VERSION 5.7 ;
  NOWIREEXTENSIONATPIN ON ;
  DIVIDERCHAR "/" ;
  BUSBITCHARS "[]" ;
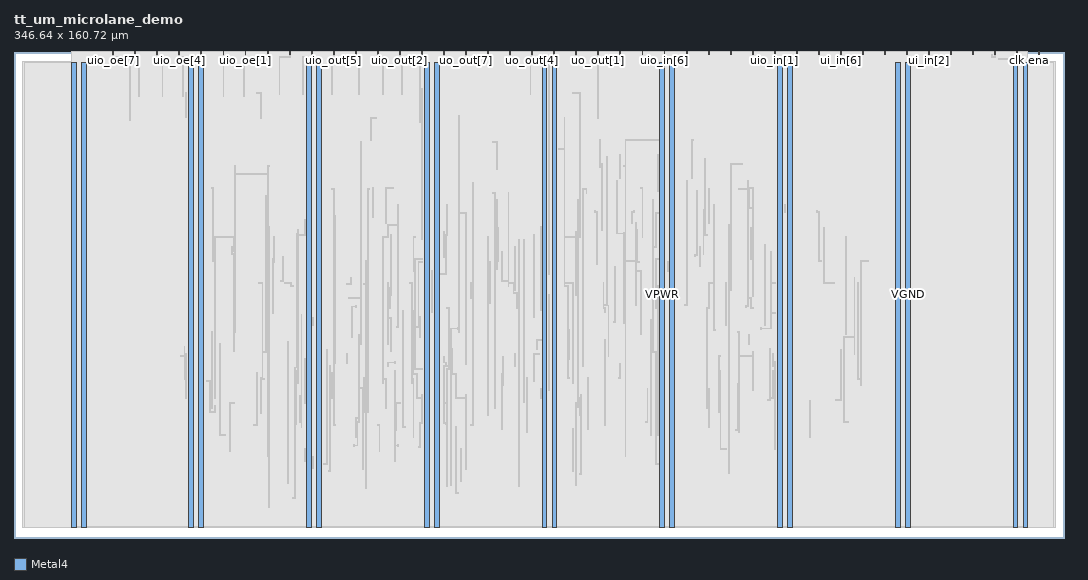
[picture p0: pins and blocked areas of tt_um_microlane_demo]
MACRO tt_um_microlane_demo
  CLASS BLOCK ;
  FOREIGN tt_um_microlane_demo ;
  ORIGIN 0.000 0.000 ;
  SIZE 346.640 BY 160.720 ;
  PIN VPWR
    DIRECTION INOUT ;
    USE POWER ;
    PORT
      LAYER Metal4 ;
        RECT 18.880 3.620 20.480 157.100 ;
    END
    PORT
      LAYER Metal4 ;
        RECT 57.750 3.620 59.350 157.100 ;
    END
    PORT
      LAYER Metal4 ;
        RECT 96.620 3.620 98.220 157.100 ;
    END
    PORT
      LAYER Metal4 ;
        RECT 135.490 3.620 137.090 157.100 ;
    END
    PORT
      LAYER Metal4 ;
        RECT 174.360 3.620 175.960 157.100 ;
    END
    PORT
      LAYER Metal4 ;
        RECT 213.230 3.620 214.830 157.100 ;
    END
    PORT
      LAYER Metal4 ;
        RECT 252.100 3.620 253.700 157.100 ;
    END
    PORT
      LAYER Metal4 ;
        RECT 290.970 3.620 292.570 157.100 ;
    END
    PORT
      LAYER Metal4 ;
        RECT 329.840 3.620 331.440 157.100 ;
    END
  END VPWR
  PIN VGND
    DIRECTION INOUT ;
    USE GROUND ;
    PORT
      LAYER Metal4 ;
        RECT 22.180 3.620 23.780 157.100 ;
    END
    PORT
      LAYER Metal4 ;
        RECT 61.050 3.620 62.650 157.100 ;
    END
    PORT
      LAYER Metal4 ;
        RECT 99.920 3.620 101.520 157.100 ;
    END
    PORT
      LAYER Metal4 ;
        RECT 138.790 3.620 140.390 157.100 ;
    END
    PORT
      LAYER Metal4 ;
        RECT 177.660 3.620 179.260 157.100 ;
    END
    PORT
      LAYER Metal4 ;
        RECT 216.530 3.620 218.130 157.100 ;
    END
    PORT
      LAYER Metal4 ;
        RECT 255.400 3.620 257.000 157.100 ;
    END
    PORT
      LAYER Metal4 ;
        RECT 294.270 3.620 295.870 157.100 ;
    END
    PORT
      LAYER Metal4 ;
        RECT 333.140 3.620 334.740 157.100 ;
    END
  END VGND
  PIN ena
    DIRECTION INPUT ;
    USE SIGNAL ;
    PORT
      LAYER Metal4 ;
        RECT 338.370 159.720 338.670 160.720 ;
    END
  END ena
  PIN clk
    DIRECTION INPUT ;
    USE SIGNAL ;
    PORT
      LAYER Metal4 ;
        RECT 331.090 159.720 331.390 160.720 ;
    END
  END clk
  PIN rst_n
    DIRECTION INPUT ;
    USE SIGNAL ;
    PORT
      LAYER Metal4 ;
        RECT 323.810 159.720 324.110 160.720 ;
    END
  END rst_n
  PIN ui_in[0]
    DIRECTION INPUT ;
    USE SIGNAL ;
    PORT
      LAYER Metal4 ;
        RECT 316.530 159.720 316.830 160.720 ;
    END
  END ui_in[0]
  PIN ui_in[1]
    DIRECTION INPUT ;
    USE SIGNAL ;
    PORT
      LAYER Metal4 ;
        RECT 309.250 159.720 309.550 160.720 ;
    END
  END ui_in[1]
  PIN ui_in[2]
    DIRECTION INPUT ;
    USE SIGNAL ;
    PORT
      LAYER Metal4 ;
        RECT 301.970 159.720 302.270 160.720 ;
    END
  END ui_in[2]
  PIN ui_in[3]
    DIRECTION INPUT ;
    USE SIGNAL ;
    PORT
      LAYER Metal4 ;
        RECT 294.690 159.720 294.990 160.720 ;
    END
  END ui_in[3]
  PIN ui_in[4]
    DIRECTION INPUT ;
    USE SIGNAL ;
    PORT
      LAYER Metal4 ;
        RECT 287.410 159.720 287.710 160.720 ;
    END
  END ui_in[4]
  PIN ui_in[5]
    DIRECTION INPUT ;
    USE SIGNAL ;
    PORT
      LAYER Metal4 ;
        RECT 280.130 159.720 280.430 160.720 ;
    END
  END ui_in[5]
  PIN ui_in[6]
    DIRECTION INPUT ;
    USE SIGNAL ;
    PORT
      LAYER Metal4 ;
        RECT 272.850 159.720 273.150 160.720 ;
    END
  END ui_in[6]
  PIN ui_in[7]
    DIRECTION INPUT ;
    USE SIGNAL ;
    PORT
      LAYER Metal4 ;
        RECT 265.570 159.720 265.870 160.720 ;
    END
  END ui_in[7]
  PIN uio_in[0]
    DIRECTION INPUT ;
    USE SIGNAL ;
    PORT
      LAYER Metal4 ;
        RECT 258.290 159.720 258.590 160.720 ;
    END
  END uio_in[0]
  PIN uio_in[1]
    DIRECTION INPUT ;
    USE SIGNAL ;
    PORT
      LAYER Metal4 ;
        RECT 251.010 159.720 251.310 160.720 ;
    END
  END uio_in[1]
  PIN uio_in[2]
    DIRECTION INPUT ;
    USE SIGNAL ;
    PORT
      LAYER Metal4 ;
        RECT 243.730 159.720 244.030 160.720 ;
    END
  END uio_in[2]
  PIN uio_in[3]
    DIRECTION INPUT ;
    USE SIGNAL ;
    PORT
      LAYER Metal4 ;
        RECT 236.450 159.720 236.750 160.720 ;
    END
  END uio_in[3]
  PIN uio_in[4]
    DIRECTION INPUT ;
    USE SIGNAL ;
    PORT
      LAYER Metal4 ;
        RECT 229.170 159.720 229.470 160.720 ;
    END
  END uio_in[4]
  PIN uio_in[5]
    DIRECTION INPUT ;
    USE SIGNAL ;
    PORT
      LAYER Metal4 ;
        RECT 221.890 159.720 222.190 160.720 ;
    END
  END uio_in[5]
  PIN uio_in[6]
    DIRECTION INPUT ;
    USE SIGNAL ;
    PORT
      LAYER Metal4 ;
        RECT 214.610 159.720 214.910 160.720 ;
    END
  END uio_in[6]
  PIN uio_in[7]
    DIRECTION INPUT ;
    USE SIGNAL ;
    PORT
      LAYER Metal4 ;
        RECT 207.330 159.720 207.630 160.720 ;
    END
  END uio_in[7]
  PIN uo_out[0]
    DIRECTION OUTPUT ;
    USE SIGNAL ;
    PORT
      LAYER Metal4 ;
        RECT 200.050 159.720 200.350 160.720 ;
    END
  END uo_out[0]
  PIN uo_out[1]
    DIRECTION OUTPUT ;
    USE SIGNAL ;
    PORT
      LAYER Metal4 ;
        RECT 192.770 159.720 193.070 160.720 ;
    END
  END uo_out[1]
  PIN uo_out[2]
    DIRECTION OUTPUT ;
    USE SIGNAL ;
    PORT
      LAYER Metal4 ;
        RECT 185.490 159.720 185.790 160.720 ;
    END
  END uo_out[2]
  PIN uo_out[3]
    DIRECTION OUTPUT ;
    USE SIGNAL ;
    PORT
      LAYER Metal4 ;
        RECT 178.210 159.720 178.510 160.720 ;
    END
  END uo_out[3]
  PIN uo_out[4]
    DIRECTION OUTPUT ;
    USE SIGNAL ;
    PORT
      LAYER Metal4 ;
        RECT 170.930 159.720 171.230 160.720 ;
    END
  END uo_out[4]
  PIN uo_out[5]
    DIRECTION OUTPUT ;
    USE SIGNAL ;
    PORT
      LAYER Metal4 ;
        RECT 163.650 159.720 163.950 160.720 ;
    END
  END uo_out[5]
  PIN uo_out[6]
    DIRECTION OUTPUT ;
    USE SIGNAL ;
    PORT
      LAYER Metal4 ;
        RECT 156.370 159.720 156.670 160.720 ;
    END
  END uo_out[6]
  PIN uo_out[7]
    DIRECTION OUTPUT ;
    USE SIGNAL ;
    PORT
      LAYER Metal4 ;
        RECT 149.090 159.720 149.390 160.720 ;
    END
  END uo_out[7]
  PIN uio_out[0]
    DIRECTION OUTPUT ;
    USE SIGNAL ;
    PORT
      LAYER Metal4 ;
        RECT 141.810 159.720 142.110 160.720 ;
    END
  END uio_out[0]
  PIN uio_out[1]
    DIRECTION OUTPUT ;
    USE SIGNAL ;
    PORT
      LAYER Metal4 ;
        RECT 134.530 159.720 134.830 160.720 ;
    END
  END uio_out[1]
  PIN uio_out[2]
    DIRECTION OUTPUT ;
    USE SIGNAL ;
    PORT
      LAYER Metal4 ;
        RECT 127.250 159.720 127.550 160.720 ;
    END
  END uio_out[2]
  PIN uio_out[3]
    DIRECTION OUTPUT ;
    USE SIGNAL ;
    PORT
      LAYER Metal4 ;
        RECT 119.970 159.720 120.270 160.720 ;
    END
  END uio_out[3]
  PIN uio_out[4]
    DIRECTION OUTPUT ;
    USE SIGNAL ;
    PORT
      LAYER Metal4 ;
        RECT 112.690 159.720 112.990 160.720 ;
    END
  END uio_out[4]
  PIN uio_out[5]
    DIRECTION OUTPUT ;
    USE SIGNAL ;
    PORT
      LAYER Metal4 ;
        RECT 105.410 159.720 105.710 160.720 ;
    END
  END uio_out[5]
  PIN uio_out[6]
    DIRECTION OUTPUT ;
    USE SIGNAL ;
    PORT
      LAYER Metal4 ;
        RECT 98.130 159.720 98.430 160.720 ;
    END
  END uio_out[6]
  PIN uio_out[7]
    DIRECTION OUTPUT ;
    USE SIGNAL ;
    PORT
      LAYER Metal4 ;
        RECT 90.850 159.720 91.150 160.720 ;
    END
  END uio_out[7]
  PIN uio_oe[0]
    DIRECTION OUTPUT ;
    USE SIGNAL ;
    PORT
      LAYER Metal4 ;
        RECT 83.570 159.720 83.870 160.720 ;
    END
  END uio_oe[0]
  PIN uio_oe[1]
    DIRECTION OUTPUT ;
    USE SIGNAL ;
    PORT
      LAYER Metal4 ;
        RECT 76.290 159.720 76.590 160.720 ;
    END
  END uio_oe[1]
  PIN uio_oe[2]
    DIRECTION OUTPUT ;
    USE SIGNAL ;
    PORT
      LAYER Metal4 ;
        RECT 69.010 159.720 69.310 160.720 ;
    END
  END uio_oe[2]
  PIN uio_oe[3]
    DIRECTION OUTPUT ;
    USE SIGNAL ;
    PORT
      LAYER Metal4 ;
        RECT 61.730 159.720 62.030 160.720 ;
    END
  END uio_oe[3]
  PIN uio_oe[4]
    DIRECTION OUTPUT ;
    USE SIGNAL ;
    PORT
      LAYER Metal4 ;
        RECT 54.450 159.720 54.750 160.720 ;
    END
  END uio_oe[4]
  PIN uio_oe[5]
    DIRECTION OUTPUT ;
    USE SIGNAL ;
    PORT
      LAYER Metal4 ;
        RECT 47.170 159.720 47.470 160.720 ;
    END
  END uio_oe[5]
  PIN uio_oe[6]
    DIRECTION OUTPUT ;
    USE SIGNAL ;
    PORT
      LAYER Metal4 ;
        RECT 39.890 159.720 40.190 160.720 ;
    END
  END uio_oe[6]
  PIN uio_oe[7]
    DIRECTION OUTPUT ;
    USE SIGNAL ;
    PORT
      LAYER Metal4 ;
        RECT 32.610 159.720 32.910 160.720 ;
    END
  END uio_oe[7]
  OBS
      LAYER Nwell ;
        RECT 2.930 3.490 343.710 157.230 ;
      LAYER Pwell ;
        RECT 2.930 3.490 343.710 157.230 ;
      LAYER Metal1 ;
        RECT 3.360 3.620 343.280 157.100 ;
      LAYER Metal2 ;
        RECT 19.020 3.730 334.600 158.950 ;
      LAYER Metal3 ;
        RECT 18.970 3.780 334.650 160.580 ;
      LAYER Metal4 ;
        RECT 18.880 3.620 20.480 157.100 ;
        RECT 57.750 3.620 59.350 157.100 ;
        RECT 96.620 3.620 98.220 157.100 ;
        RECT 135.490 3.620 137.090 157.100 ;
        RECT 174.360 3.620 175.960 157.100 ;
        RECT 213.230 3.620 214.830 157.100 ;
        RECT 252.100 3.620 253.700 157.100 ;
        RECT 290.970 3.620 292.570 157.100 ;
        RECT 329.840 3.620 331.440 157.100 ;
        RECT 22.180 3.620 23.780 157.100 ;
        RECT 61.050 3.620 62.650 157.100 ;
        RECT 99.920 3.620 101.520 157.100 ;
        RECT 138.790 3.620 140.390 157.100 ;
        RECT 177.660 3.620 179.260 157.100 ;
        RECT 216.530 3.620 218.130 157.100 ;
        RECT 255.400 3.620 257.000 157.100 ;
        RECT 294.270 3.620 295.870 157.100 ;
        RECT 333.140 3.620 334.740 157.100 ;
        RECT 338.370 159.460 338.670 160.720 ;
        RECT 331.090 159.460 331.390 160.720 ;
        RECT 323.810 159.460 324.110 160.720 ;
        RECT 316.530 159.460 316.830 160.720 ;
        RECT 309.250 159.460 309.550 160.720 ;
        RECT 301.970 159.460 302.270 160.720 ;
        RECT 294.690 159.460 294.990 160.720 ;
        RECT 287.410 159.460 287.710 160.720 ;
        RECT 280.130 159.460 280.430 160.720 ;
        RECT 272.850 159.460 273.150 160.720 ;
        RECT 265.570 159.460 265.870 160.720 ;
        RECT 258.290 159.460 258.590 160.720 ;
        RECT 251.010 159.460 251.310 160.720 ;
        RECT 243.730 159.460 244.030 160.720 ;
        RECT 236.450 159.460 236.750 160.720 ;
        RECT 229.170 159.460 229.470 160.720 ;
        RECT 221.890 159.460 222.190 160.720 ;
        RECT 214.610 159.460 214.910 160.720 ;
        RECT 207.330 159.460 207.630 160.720 ;
        RECT 200.050 159.460 200.350 160.720 ;
        RECT 192.770 159.460 193.070 160.720 ;
        RECT 185.490 159.460 185.790 160.720 ;
        RECT 178.210 159.460 178.510 160.720 ;
        RECT 170.930 159.460 171.230 160.720 ;
        RECT 163.650 159.460 163.950 160.720 ;
        RECT 156.370 159.460 156.670 160.720 ;
        RECT 149.090 159.460 149.390 160.720 ;
        RECT 141.810 159.460 142.110 160.720 ;
        RECT 134.530 159.460 134.830 160.720 ;
        RECT 127.250 159.460 127.550 160.720 ;
        RECT 119.970 159.460 120.270 160.720 ;
        RECT 112.690 159.460 112.990 160.720 ;
        RECT 105.410 159.460 105.710 160.720 ;
        RECT 98.130 159.460 98.430 160.720 ;
        RECT 90.850 159.460 91.150 160.720 ;
        RECT 83.570 159.460 83.870 160.720 ;
        RECT 76.290 159.460 76.590 160.720 ;
        RECT 69.010 159.460 69.310 160.720 ;
        RECT 61.730 159.460 62.030 160.720 ;
        RECT 54.450 159.460 54.750 160.720 ;
        RECT 47.170 159.460 47.470 160.720 ;
        RECT 39.890 159.460 40.190 160.720 ;
        RECT 32.610 159.460 32.910 160.720 ;
        RECT 184.380 146.810 184.660 147.190 ;
        RECT 184.380 146.860 184.660 147.140 ;
        RECT 184.380 146.860 186.900 147.140 ;
        RECT 186.620 99.210 186.900 99.590 ;
        RECT 186.620 99.260 186.900 99.540 ;
        RECT 186.620 99.260 186.900 147.140 ;
        RECT 182.140 84.090 182.420 84.470 ;
        RECT 182.140 84.140 182.420 84.420 ;
        RECT 182.140 84.140 184.660 84.420 ;
        RECT 184.380 51.050 184.660 51.430 ;
        RECT 184.380 51.100 184.660 51.380 ;
        RECT 184.380 51.100 184.660 84.420 ;
        RECT 146.860 138.970 147.140 139.350 ;
        RECT 146.860 67.850 147.140 68.230 ;
        RECT 146.860 67.900 147.140 68.180 ;
        RECT 146.860 67.900 147.140 139.300 ;
        RECT 146.860 139.020 147.140 139.300 ;
        RECT 85.820 99.210 86.100 99.590 ;
        RECT 85.820 90.810 86.100 91.190 ;
        RECT 85.820 90.860 86.100 91.140 ;
        RECT 85.820 90.860 86.100 99.540 ;
        RECT 85.820 99.260 86.100 99.540 ;
        RECT 142.380 99.770 142.660 100.150 ;
        RECT 140.700 86.890 140.980 87.270 ;
        RECT 140.700 86.940 140.980 87.220 ;
        RECT 140.700 86.940 142.660 87.220 ;
        RECT 142.380 86.940 142.660 100.100 ;
        RECT 142.380 99.820 142.660 100.100 ;
        RECT 142.380 99.820 143.220 100.100 ;
        RECT 142.940 99.820 143.220 110.180 ;
        RECT 142.940 109.850 143.220 110.230 ;
        RECT 142.940 109.900 143.220 110.180 ;
        RECT 231.420 68.410 231.700 68.790 ;
        RECT 230.860 68.460 231.140 110.180 ;
        RECT 230.860 68.460 231.700 68.740 ;
        RECT 230.860 109.850 231.140 110.230 ;
        RECT 230.860 109.900 231.140 110.180 ;
        RECT 231.420 68.460 231.700 68.740 ;
        RECT 134.540 91.930 134.820 92.310 ;
        RECT 132.300 55.580 132.580 82.180 ;
        RECT 132.300 55.580 134.820 55.860 ;
        RECT 132.300 81.850 132.580 82.230 ;
        RECT 132.300 81.900 132.580 82.180 ;
        RECT 132.300 81.900 132.580 92.260 ;
        RECT 132.300 91.980 134.820 92.260 ;
        RECT 134.540 55.530 134.820 55.910 ;
        RECT 134.540 55.580 134.820 55.860 ;
        RECT 134.540 91.980 134.820 92.260 ;
        RECT 85.260 91.930 85.540 92.310 ;
        RECT 85.260 74.010 85.540 74.390 ;
        RECT 85.260 74.060 85.540 74.340 ;
        RECT 85.260 74.060 85.540 92.260 ;
        RECT 85.260 91.980 85.540 92.260 ;
        RECT 112.700 76.250 112.980 76.630 ;
        RECT 111.580 66.170 111.860 66.550 ;
        RECT 111.580 66.220 111.860 66.500 ;
        RECT 111.580 66.220 111.860 76.580 ;
        RECT 111.580 76.300 112.980 76.580 ;
        RECT 112.700 76.300 112.980 76.580 ;
        RECT 98.700 72.330 98.980 72.710 ;
        RECT 98.700 70.090 98.980 70.470 ;
        RECT 98.700 70.140 98.980 70.420 ;
        RECT 98.700 70.140 98.980 72.660 ;
        RECT 98.700 72.380 98.980 72.660 ;
        RECT 132.860 69.530 133.140 69.910 ;
        RECT 132.860 69.580 133.140 69.860 ;
        RECT 132.860 69.580 133.700 69.860 ;
        RECT 133.420 69.580 133.700 76.020 ;
        RECT 133.420 75.690 133.700 76.070 ;
        RECT 133.420 75.740 133.700 76.020 ;
        RECT 133.420 75.740 133.700 91.140 ;
        RECT 133.420 90.860 134.820 91.140 ;
        RECT 134.540 90.810 134.820 91.190 ;
        RECT 134.540 90.860 134.820 91.140 ;
        RECT 89.180 84.090 89.460 84.470 ;
        RECT 89.180 84.140 89.460 84.420 ;
        RECT 89.180 84.140 91.700 84.420 ;
        RECT 91.420 83.020 91.700 84.420 ;
        RECT 91.420 83.020 92.260 83.300 ;
        RECT 91.980 82.970 92.260 83.350 ;
        RECT 91.980 83.020 92.260 83.300 ;
        RECT 186.620 20.810 186.900 21.190 ;
        RECT 186.620 20.860 186.900 21.140 ;
        RECT 186.620 20.860 187.460 21.140 ;
        RECT 187.180 20.860 187.460 47.460 ;
        RECT 187.180 47.130 187.460 47.510 ;
        RECT 187.180 47.180 187.460 47.460 ;
        RECT 79.100 37.050 79.380 37.430 ;
        RECT 79.100 37.100 79.380 37.380 ;
        RECT 79.100 37.100 80.500 37.380 ;
        RECT 80.220 37.100 80.500 54.740 ;
        RECT 80.220 54.410 80.500 54.790 ;
        RECT 80.220 54.460 80.500 54.740 ;
        RECT 93.100 37.610 93.380 37.990 ;
        RECT 93.100 37.660 93.380 37.940 ;
        RECT 93.100 37.660 93.380 55.300 ;
        RECT 93.100 54.970 93.380 55.350 ;
        RECT 93.100 55.020 93.380 55.300 ;
        RECT 142.380 37.610 142.660 37.990 ;
        RECT 141.820 37.660 142.100 56.980 ;
        RECT 141.820 37.660 142.660 37.940 ;
        RECT 141.820 56.650 142.100 57.030 ;
        RECT 141.820 56.700 142.100 56.980 ;
        RECT 142.380 37.660 142.660 37.940 ;
        RECT 127.260 44.330 127.540 44.710 ;
        RECT 126.140 35.370 126.420 35.750 ;
        RECT 126.140 35.420 126.420 35.700 ;
        RECT 126.140 35.420 126.420 44.660 ;
        RECT 126.140 44.380 127.540 44.660 ;
        RECT 127.260 44.380 127.540 44.660 ;
        RECT 169.260 52.730 169.540 53.110 ;
        RECT 169.260 34.810 169.540 35.190 ;
        RECT 169.260 34.860 169.540 35.140 ;
        RECT 169.260 34.860 169.540 53.060 ;
        RECT 169.260 52.780 169.540 53.060 ;
        RECT 126.140 69.530 126.420 69.910 ;
        RECT 126.140 69.580 126.420 69.860 ;
        RECT 126.140 69.580 126.980 69.860 ;
        RECT 126.700 69.580 126.980 110.180 ;
        RECT 126.700 71.770 126.980 72.150 ;
        RECT 126.700 71.820 126.980 72.100 ;
        RECT 126.700 109.850 126.980 110.230 ;
        RECT 126.700 109.900 126.980 110.180 ;
        RECT 119.420 138.410 119.700 138.790 ;
        RECT 117.740 131.130 118.020 131.510 ;
        RECT 117.740 131.180 118.020 131.460 ;
        RECT 117.740 131.180 118.020 138.740 ;
        RECT 117.740 138.460 119.700 138.740 ;
        RECT 119.420 138.460 119.700 138.740 ;
        RECT 183.260 52.730 183.540 53.110 ;
        RECT 179.900 128.330 180.180 128.710 ;
        RECT 179.900 128.380 180.180 128.660 ;
        RECT 179.900 128.380 181.860 128.660 ;
        RECT 181.580 83.020 181.860 99.540 ;
        RECT 181.580 83.020 182.980 83.300 ;
        RECT 181.580 99.260 181.860 130.900 ;
        RECT 181.580 99.260 185.220 99.540 ;
        RECT 181.580 130.570 181.860 130.950 ;
        RECT 181.580 130.620 181.860 130.900 ;
        RECT 181.580 130.620 181.860 138.740 ;
        RECT 181.580 138.410 181.860 138.790 ;
        RECT 181.580 138.460 181.860 138.740 ;
        RECT 182.700 52.780 182.980 63.140 ;
        RECT 182.700 52.780 183.540 53.060 ;
        RECT 182.700 62.810 182.980 63.190 ;
        RECT 182.700 62.860 182.980 63.140 ;
        RECT 182.700 62.860 182.980 83.300 ;
        RECT 183.260 52.780 183.540 53.060 ;
        RECT 184.940 99.210 185.220 99.590 ;
        RECT 184.940 99.260 185.220 99.540 ;
        RECT 122.220 52.170 122.500 52.550 ;
        RECT 122.220 52.220 122.500 52.500 ;
        RECT 122.220 52.220 123.060 52.500 ;
        RECT 122.780 42.650 123.060 43.030 ;
        RECT 122.780 42.700 123.060 42.980 ;
        RECT 122.780 42.700 123.060 52.500 ;
        RECT 102.060 24.170 102.340 24.550 ;
        RECT 102.060 24.220 102.340 24.500 ;
        RECT 102.060 24.220 103.460 24.500 ;
        RECT 103.180 24.220 103.460 62.020 ;
        RECT 103.180 61.690 103.460 62.070 ;
        RECT 103.180 61.740 103.460 62.020 ;
        RECT 114.380 130.570 114.660 130.950 ;
        RECT 114.380 63.930 114.660 64.310 ;
        RECT 114.380 63.980 114.660 64.260 ;
        RECT 114.380 63.980 114.660 130.900 ;
        RECT 114.380 130.620 114.660 130.900 ;
        RECT 195.020 76.810 195.300 77.190 ;
        RECT 195.020 76.860 195.300 77.140 ;
        RECT 195.020 76.860 195.860 77.140 ;
        RECT 195.580 76.860 195.860 125.860 ;
        RECT 195.580 125.530 195.860 125.910 ;
        RECT 195.580 125.580 195.860 125.860 ;
        RECT 84.140 122.730 84.420 123.110 ;
        RECT 83.580 26.970 83.860 27.350 ;
        RECT 83.580 27.020 83.860 27.300 ;
        RECT 83.580 27.020 83.860 123.060 ;
        RECT 83.580 122.780 84.420 123.060 ;
        RECT 84.140 122.780 84.420 123.060 ;
        RECT 98.700 26.410 98.980 26.790 ;
        RECT 98.700 23.050 98.980 23.430 ;
        RECT 98.700 23.100 98.980 23.380 ;
        RECT 98.700 23.100 98.980 26.740 ;
        RECT 98.700 26.460 98.980 26.740 ;
        RECT 158.060 130.570 158.340 130.950 ;
        RECT 158.060 130.620 158.340 130.900 ;
        RECT 158.060 130.620 159.460 130.900 ;
        RECT 159.180 121.610 159.460 121.990 ;
        RECT 159.180 121.660 159.460 121.940 ;
        RECT 159.180 121.660 159.460 130.900 ;
        RECT 201.740 60.010 202.020 60.390 ;
        RECT 201.180 122.730 201.460 123.110 ;
        RECT 201.180 122.780 201.460 123.060 ;
        RECT 201.180 122.780 202.020 123.060 ;
        RECT 201.740 26.970 202.020 27.350 ;
        RECT 201.740 27.020 202.020 27.300 ;
        RECT 201.740 27.020 202.020 60.340 ;
        RECT 201.740 60.060 202.020 60.340 ;
        RECT 201.740 60.060 202.020 91.700 ;
        RECT 201.740 91.420 202.020 123.060 ;
        RECT 201.740 91.420 204.820 91.700 ;
        RECT 201.740 122.780 202.020 131.460 ;
        RECT 201.740 131.180 212.660 131.460 ;
        RECT 204.540 91.370 204.820 91.750 ;
        RECT 204.540 91.420 204.820 91.700 ;
        RECT 212.380 131.130 212.660 131.510 ;
        RECT 212.380 131.180 212.660 131.460 ;
        RECT 65.100 67.850 65.380 68.230 ;
        RECT 65.100 42.650 65.380 43.030 ;
        RECT 65.100 42.700 65.380 42.980 ;
        RECT 65.100 42.700 65.380 68.180 ;
        RECT 65.100 67.900 65.380 68.180 ;
        RECT 72.940 122.730 73.220 123.110 ;
        RECT 72.940 67.850 73.220 68.230 ;
        RECT 72.940 67.900 73.220 68.180 ;
        RECT 72.940 67.900 73.220 123.060 ;
        RECT 72.940 119.980 83.300 120.260 ;
        RECT 72.940 122.780 73.220 123.060 ;
        RECT 83.020 119.930 83.300 120.310 ;
        RECT 83.020 119.980 83.300 120.260 ;
        RECT 221.340 76.810 221.620 77.190 ;
        RECT 221.340 76.860 221.620 77.140 ;
        RECT 221.340 76.860 222.180 77.140 ;
        RECT 221.900 76.860 222.180 118.020 ;
        RECT 221.900 117.690 222.180 118.070 ;
        RECT 221.900 117.740 222.180 118.020 ;
        RECT 94.220 38.170 94.500 38.550 ;
        RECT 94.220 38.220 94.500 38.500 ;
        RECT 94.220 38.220 94.500 46.900 ;
        RECT 94.220 46.570 94.500 46.950 ;
        RECT 94.220 46.620 94.500 46.900 ;
        RECT 113.260 38.170 113.540 38.550 ;
        RECT 112.140 30.330 112.420 30.710 ;
        RECT 112.140 30.380 112.420 30.660 ;
        RECT 112.140 30.380 113.540 30.660 ;
        RECT 113.260 30.380 113.540 38.500 ;
        RECT 113.260 38.220 113.540 38.500 ;
        RECT 113.260 38.220 114.100 38.500 ;
        RECT 113.820 38.220 114.100 67.060 ;
        RECT 113.820 48.250 114.100 48.630 ;
        RECT 113.820 48.300 114.100 48.580 ;
        RECT 113.820 66.730 114.100 67.110 ;
        RECT 113.820 66.780 114.100 67.060 ;
        RECT 201.180 100.330 201.460 100.710 ;
        RECT 198.940 100.380 199.220 118.020 ;
        RECT 198.940 100.380 201.460 100.660 ;
        RECT 198.940 117.690 199.220 118.070 ;
        RECT 198.940 117.740 199.220 118.020 ;
        RECT 201.180 70.650 201.460 71.030 ;
        RECT 201.180 70.700 201.460 70.980 ;
        RECT 201.180 70.700 201.460 100.660 ;
        RECT 201.180 100.380 201.460 100.660 ;
        RECT 239.260 114.890 239.540 115.270 ;
        RECT 239.260 114.940 239.540 115.220 ;
        RECT 239.260 114.940 242.340 115.220 ;
        RECT 241.500 76.250 241.780 76.630 ;
        RECT 241.500 76.300 241.780 76.580 ;
        RECT 241.500 76.300 242.340 76.580 ;
        RECT 242.060 76.300 242.340 115.220 ;
        RECT 94.780 43.770 95.060 44.150 ;
        RECT 94.780 36.490 95.060 36.870 ;
        RECT 94.780 36.540 95.060 36.820 ;
        RECT 94.780 36.540 95.060 44.100 ;
        RECT 94.780 43.820 95.060 44.100 ;
        RECT 94.780 43.820 95.060 73.780 ;
        RECT 94.780 73.450 95.060 73.830 ;
        RECT 94.780 73.500 95.060 73.780 ;
        RECT 133.980 66.170 134.260 66.550 ;
        RECT 133.980 66.220 134.260 66.500 ;
        RECT 133.980 66.220 134.260 73.220 ;
        RECT 133.980 72.890 134.260 73.270 ;
        RECT 133.980 72.940 134.260 73.220 ;
        RECT 95.900 29.210 96.180 29.590 ;
        RECT 95.900 25.290 96.180 25.670 ;
        RECT 95.900 25.340 96.180 25.620 ;
        RECT 95.900 25.340 96.180 29.540 ;
        RECT 95.900 29.260 96.180 29.540 ;
        RECT 126.700 30.330 126.980 30.710 ;
        RECT 125.580 25.290 125.860 25.670 ;
        RECT 125.580 25.340 125.860 25.620 ;
        RECT 125.580 25.340 125.860 30.660 ;
        RECT 125.580 30.380 125.860 55.300 ;
        RECT 125.580 30.380 126.980 30.660 ;
        RECT 125.580 54.970 125.860 55.350 ;
        RECT 125.580 55.020 125.860 55.300 ;
        RECT 126.700 30.380 126.980 30.660 ;
        RECT 72.380 44.330 72.660 44.710 ;
        RECT 71.260 28.650 71.540 29.030 ;
        RECT 71.260 28.700 71.540 28.980 ;
        RECT 71.260 28.700 71.540 44.660 ;
        RECT 71.260 44.380 72.660 44.660 ;
        RECT 72.380 44.380 72.660 44.660 ;
        RECT 66.220 83.530 66.500 83.910 ;
        RECT 66.220 46.010 66.500 46.390 ;
        RECT 66.220 46.060 66.500 46.340 ;
        RECT 66.220 46.060 66.500 83.860 ;
        RECT 66.220 83.580 66.500 83.860 ;
        RECT 66.220 83.580 66.500 99.540 ;
        RECT 66.220 99.260 69.300 99.540 ;
        RECT 69.020 99.210 69.300 99.590 ;
        RECT 69.020 99.260 69.300 99.540 ;
        RECT 69.020 99.260 72.660 99.540 ;
        RECT 72.380 94.730 72.660 95.110 ;
        RECT 72.380 94.780 72.660 95.060 ;
        RECT 72.380 94.780 72.660 99.540 ;
        RECT 72.380 99.210 72.660 99.590 ;
        RECT 72.380 99.260 72.660 99.540 ;
        RECT 162.540 84.650 162.820 85.030 ;
        RECT 160.860 84.700 161.140 94.500 ;
        RECT 160.860 84.700 162.820 84.980 ;
        RECT 160.860 94.170 161.140 94.550 ;
        RECT 160.860 94.220 161.140 94.500 ;
        RECT 162.540 84.700 162.820 84.980 ;
        RECT 251.020 84.090 251.300 84.470 ;
        RECT 246.540 68.970 246.820 69.350 ;
        RECT 246.540 69.020 246.820 69.300 ;
        RECT 246.540 69.020 250.180 69.300 ;
        RECT 249.900 69.020 250.180 84.420 ;
        RECT 249.900 74.060 251.300 74.340 ;
        RECT 249.900 84.140 250.180 94.500 ;
        RECT 249.900 84.140 251.300 84.420 ;
        RECT 249.900 94.170 250.180 94.550 ;
        RECT 249.900 94.220 250.180 94.500 ;
        RECT 251.020 74.010 251.300 74.390 ;
        RECT 251.020 74.060 251.300 74.340 ;
        RECT 251.020 84.140 251.300 84.420 ;
        RECT 123.340 84.090 123.620 84.470 ;
        RECT 123.340 63.930 123.620 64.310 ;
        RECT 123.340 63.980 123.620 64.260 ;
        RECT 123.340 63.980 123.620 84.420 ;
        RECT 123.340 84.140 123.620 84.420 ;
        RECT 145.740 53.850 146.020 54.230 ;
        RECT 144.620 53.900 144.900 62.580 ;
        RECT 144.620 53.900 146.020 54.180 ;
        RECT 144.620 62.250 144.900 62.630 ;
        RECT 144.620 62.300 144.900 62.580 ;
        RECT 145.740 46.060 146.020 54.180 ;
        RECT 145.740 46.060 148.820 46.340 ;
        RECT 145.740 53.900 146.020 54.180 ;
        RECT 148.540 46.010 148.820 46.390 ;
        RECT 148.540 46.060 148.820 46.340 ;
        RECT 132.300 99.210 132.580 99.590 ;
        RECT 131.740 88.010 132.020 88.390 ;
        RECT 131.740 88.060 132.020 88.340 ;
        RECT 131.740 88.060 132.020 99.540 ;
        RECT 131.740 99.260 132.580 99.540 ;
        RECT 132.300 99.260 132.580 99.540 ;
        RECT 137.900 88.010 138.180 88.390 ;
        RECT 137.900 74.570 138.180 74.950 ;
        RECT 137.900 74.620 138.180 74.900 ;
        RECT 137.900 74.620 138.180 88.340 ;
        RECT 137.900 88.060 138.180 88.340 ;
        RECT 173.740 102.570 174.020 102.950 ;
        RECT 173.740 75.130 174.020 75.510 ;
        RECT 173.740 75.180 174.020 75.460 ;
        RECT 173.740 75.180 174.020 102.900 ;
        RECT 173.740 102.620 174.020 102.900 ;
        RECT 243.180 91.930 243.460 92.310 ;
        RECT 243.180 91.980 243.460 92.260 ;
        RECT 243.180 91.980 243.460 102.340 ;
        RECT 243.180 102.010 243.460 102.390 ;
        RECT 243.180 102.060 243.460 102.340 ;
        RECT 132.860 53.850 133.140 54.230 ;
        RECT 131.740 53.900 132.020 74.900 ;
        RECT 131.740 53.900 133.140 54.180 ;
        RECT 131.740 74.570 132.020 74.950 ;
        RECT 131.740 74.620 132.020 74.900 ;
        RECT 132.860 46.060 133.140 54.180 ;
        RECT 132.860 46.060 134.260 46.340 ;
        RECT 132.860 53.900 133.140 54.180 ;
        RECT 133.980 46.010 134.260 46.390 ;
        RECT 133.980 46.060 134.260 46.340 ;
        RECT 165.340 91.370 165.620 91.750 ;
        RECT 165.340 81.850 165.620 82.230 ;
        RECT 165.340 81.900 165.620 82.180 ;
        RECT 165.340 81.900 165.620 91.700 ;
        RECT 165.340 91.420 165.620 91.700 ;
        RECT 165.340 91.420 165.620 96.180 ;
        RECT 165.340 95.850 165.620 96.230 ;
        RECT 165.340 95.900 165.620 96.180 ;
        RECT 212.380 107.050 212.660 107.430 ;
        RECT 211.260 95.850 211.540 96.230 ;
        RECT 211.260 95.900 211.540 96.180 ;
        RECT 211.260 95.900 212.100 96.180 ;
        RECT 211.820 95.900 212.100 107.380 ;
        RECT 211.820 107.100 212.660 107.380 ;
        RECT 212.380 107.100 212.660 107.380 ;
        RECT 270.620 84.090 270.900 84.470 ;
        RECT 267.260 84.140 267.540 102.340 ;
        RECT 267.260 84.140 270.900 84.420 ;
        RECT 267.260 102.010 267.540 102.390 ;
        RECT 267.260 102.060 267.540 102.340 ;
        RECT 270.620 84.140 270.900 84.420 ;
        RECT 55.020 60.010 55.300 60.390 ;
        RECT 55.020 60.060 55.300 60.340 ;
        RECT 55.020 60.060 56.420 60.340 ;
        RECT 56.140 52.170 56.420 52.550 ;
        RECT 56.140 52.220 56.420 52.500 ;
        RECT 56.140 52.220 56.420 60.340 ;
        RECT 72.380 83.530 72.660 83.910 ;
        RECT 71.820 93.660 72.100 96.180 ;
        RECT 71.820 93.660 72.660 93.940 ;
        RECT 71.820 95.850 72.100 96.230 ;
        RECT 71.820 95.900 72.100 96.180 ;
        RECT 72.380 61.690 72.660 62.070 ;
        RECT 72.380 61.740 72.660 62.020 ;
        RECT 72.380 61.740 72.660 83.860 ;
        RECT 72.380 83.580 72.660 83.860 ;
        RECT 72.380 83.580 72.660 93.940 ;
        RECT 277.340 60.570 277.620 60.950 ;
        RECT 277.340 60.620 277.620 60.900 ;
        RECT 277.340 60.620 277.620 86.100 ;
        RECT 277.340 85.770 277.620 86.150 ;
        RECT 277.340 85.820 277.620 86.100 ;
        RECT 103.740 21.930 104.020 22.310 ;
        RECT 103.740 21.980 104.020 22.260 ;
        RECT 103.740 21.980 104.580 22.260 ;
        RECT 104.300 21.980 104.580 31.780 ;
        RECT 104.300 31.450 104.580 31.830 ;
        RECT 104.300 31.500 104.580 31.780 ;
        RECT 104.300 31.500 104.580 56.980 ;
        RECT 104.300 56.650 104.580 57.030 ;
        RECT 104.300 56.700 104.580 56.980 ;
        RECT 123.900 82.410 124.180 82.790 ;
        RECT 123.900 75.690 124.180 76.070 ;
        RECT 123.900 75.740 124.180 76.020 ;
        RECT 123.900 75.740 124.180 82.740 ;
        RECT 123.900 82.460 124.180 82.740 ;
        RECT 128.380 74.570 128.660 74.950 ;
        RECT 128.380 36.540 128.660 74.900 ;
        RECT 128.380 36.540 129.220 36.820 ;
        RECT 128.380 74.620 128.660 74.900 ;
        RECT 128.940 36.490 129.220 36.870 ;
        RECT 128.940 36.540 129.220 36.820 ;
        RECT 95.900 99.770 96.180 100.150 ;
        RECT 93.660 51.050 93.940 51.430 ;
        RECT 93.660 51.100 93.940 51.380 ;
        RECT 93.660 51.100 93.940 100.100 ;
        RECT 93.660 99.820 96.180 100.100 ;
        RECT 95.900 99.820 96.180 100.100 ;
        RECT 95.900 99.820 96.180 105.140 ;
        RECT 95.900 104.810 96.180 105.190 ;
        RECT 95.900 104.860 96.180 105.140 ;
        RECT 114.380 49.370 114.660 49.750 ;
        RECT 114.380 49.420 114.660 49.700 ;
        RECT 114.380 49.420 115.220 49.700 ;
        RECT 114.940 22.490 115.220 22.870 ;
        RECT 114.940 22.540 115.220 22.820 ;
        RECT 114.940 22.540 115.220 49.700 ;
        RECT 205.100 76.810 205.380 77.190 ;
        RECT 205.100 76.860 205.380 77.140 ;
        RECT 205.100 76.860 205.380 104.020 ;
        RECT 205.100 103.690 205.380 104.070 ;
        RECT 205.100 103.740 205.380 104.020 ;
        RECT 229.180 114.890 229.460 115.270 ;
        RECT 229.180 103.690 229.460 104.070 ;
        RECT 229.180 103.740 229.460 104.020 ;
        RECT 229.180 103.740 229.460 115.220 ;
        RECT 229.180 114.940 229.460 115.220 ;
        RECT 235.900 21.370 236.180 21.750 ;
        RECT 235.900 21.420 236.180 21.700 ;
        RECT 235.900 21.420 236.180 103.460 ;
        RECT 235.900 103.130 236.180 103.510 ;
        RECT 235.900 103.180 236.180 103.460 ;
        RECT 109.900 83.530 110.180 83.910 ;
        RECT 109.900 83.580 110.180 83.860 ;
        RECT 109.900 83.580 111.300 83.860 ;
        RECT 111.020 83.580 111.300 86.100 ;
        RECT 111.020 85.770 111.300 86.150 ;
        RECT 111.020 85.820 111.300 86.100 ;
        RECT 105.980 57.770 106.260 58.150 ;
        RECT 105.980 57.820 106.260 58.100 ;
        RECT 105.980 57.820 106.260 106.260 ;
        RECT 105.980 105.930 106.260 106.310 ;
        RECT 105.980 105.980 106.260 106.260 ;
        RECT 211.820 61.130 212.100 61.510 ;
        RECT 210.700 61.180 210.980 111.860 ;
        RECT 210.700 61.180 212.100 61.460 ;
        RECT 210.700 111.530 210.980 111.910 ;
        RECT 210.700 111.580 210.980 111.860 ;
        RECT 211.820 24.220 212.100 61.460 ;
        RECT 211.820 24.220 212.660 24.500 ;
        RECT 211.820 61.180 212.100 61.460 ;
        RECT 212.380 24.170 212.660 24.550 ;
        RECT 212.380 24.220 212.660 24.500 ;
        RECT 104.860 114.890 105.140 115.270 ;
        RECT 104.860 114.940 105.140 115.220 ;
        RECT 104.860 114.940 105.700 115.220 ;
        RECT 105.420 37.100 105.700 99.540 ;
        RECT 105.420 37.100 106.260 37.380 ;
        RECT 105.420 99.210 105.700 99.590 ;
        RECT 105.420 99.260 105.700 99.540 ;
        RECT 105.420 99.260 105.700 115.220 ;
        RECT 105.980 37.050 106.260 37.430 ;
        RECT 105.980 37.100 106.260 37.380 ;
        RECT 188.860 114.890 189.140 115.270 ;
        RECT 187.740 56.650 188.020 57.030 ;
        RECT 187.740 56.700 188.020 56.980 ;
        RECT 187.740 56.700 188.020 97.860 ;
        RECT 187.740 97.530 188.020 97.910 ;
        RECT 187.740 97.580 188.020 97.860 ;
        RECT 187.740 97.580 188.020 115.220 ;
        RECT 187.740 114.940 189.140 115.220 ;
        RECT 188.860 113.770 189.140 114.150 ;
        RECT 188.860 113.820 189.140 114.100 ;
        RECT 188.860 113.820 189.140 115.220 ;
        RECT 188.860 114.940 189.140 115.220 ;
        RECT 212.380 123.290 212.660 123.670 ;
        RECT 212.380 114.330 212.660 114.710 ;
        RECT 212.380 114.380 212.660 114.660 ;
        RECT 212.380 114.380 212.660 123.620 ;
        RECT 212.380 123.340 212.660 123.620 ;
        RECT 212.380 123.340 212.660 126.420 ;
        RECT 212.380 126.090 212.660 126.470 ;
        RECT 212.380 126.140 212.660 126.420 ;
        RECT 228.620 99.770 228.900 100.150 ;
        RECT 228.060 99.820 228.340 125.300 ;
        RECT 228.060 99.820 228.900 100.100 ;
        RECT 228.060 124.970 228.340 125.350 ;
        RECT 228.060 125.020 228.340 125.300 ;
        RECT 228.620 99.820 228.900 100.100 ;
        RECT 234.780 29.210 235.060 29.590 ;
        RECT 233.100 29.260 233.380 55.300 ;
        RECT 233.100 29.260 235.060 29.540 ;
        RECT 233.100 54.970 233.380 55.350 ;
        RECT 233.100 55.020 233.380 55.300 ;
        RECT 234.780 29.260 235.060 29.540 ;
        RECT 119.980 37.050 120.260 37.430 ;
        RECT 119.980 37.100 120.260 37.380 ;
        RECT 119.980 37.100 120.820 37.380 ;
        RECT 120.540 28.650 120.820 29.030 ;
        RECT 120.540 28.700 120.820 28.980 ;
        RECT 120.540 28.700 120.820 37.380 ;
        RECT 117.180 114.890 117.460 115.270 ;
        RECT 116.620 41.530 116.900 41.910 ;
        RECT 116.620 41.580 116.900 41.860 ;
        RECT 116.620 41.580 116.900 115.220 ;
        RECT 116.620 114.940 117.460 115.220 ;
        RECT 117.180 114.940 117.460 115.220 ;
        RECT 186.060 107.050 186.340 107.430 ;
        RECT 186.060 43.210 186.340 43.590 ;
        RECT 186.060 43.260 186.340 43.540 ;
        RECT 186.060 43.260 186.340 107.380 ;
        RECT 186.060 107.100 186.340 107.380 ;
        RECT 186.060 107.100 186.340 111.860 ;
        RECT 186.060 111.530 186.340 111.910 ;
        RECT 186.060 111.580 186.340 111.860 ;
        RECT 229.180 75.690 229.460 76.070 ;
        RECT 228.620 42.650 228.900 43.030 ;
        RECT 228.620 42.700 228.900 42.980 ;
        RECT 228.620 42.700 228.900 76.020 ;
        RECT 228.620 75.740 229.460 76.020 ;
        RECT 229.180 75.740 229.460 76.020 ;
        RECT 229.180 75.740 229.460 84.420 ;
        RECT 229.180 84.140 230.580 84.420 ;
        RECT 230.300 84.090 230.580 84.470 ;
        RECT 230.300 84.140 230.580 84.420 ;
        RECT 131.740 52.170 132.020 52.550 ;
        RECT 131.740 33.130 132.020 33.510 ;
        RECT 131.740 33.180 132.020 33.460 ;
        RECT 131.740 33.180 132.020 52.500 ;
        RECT 131.740 52.220 132.020 52.500 ;
        RECT 159.180 107.050 159.460 107.430 ;
        RECT 159.180 88.570 159.460 88.950 ;
        RECT 159.180 88.620 159.460 88.900 ;
        RECT 159.180 88.620 159.460 107.380 ;
        RECT 159.180 107.100 159.460 107.380 ;
        RECT 159.180 107.100 159.460 111.860 ;
        RECT 159.180 111.530 159.460 111.910 ;
        RECT 159.180 111.580 159.460 111.860 ;
        RECT 206.780 83.530 207.060 83.910 ;
        RECT 205.660 88.010 205.940 88.390 ;
        RECT 205.660 88.060 205.940 88.340 ;
        RECT 205.660 88.060 207.060 88.340 ;
        RECT 206.780 67.290 207.060 67.670 ;
        RECT 206.780 67.340 207.060 67.620 ;
        RECT 206.780 67.340 207.060 83.860 ;
        RECT 206.780 83.580 207.060 83.860 ;
        RECT 206.780 83.580 207.060 88.340 ;
        RECT 238.700 67.850 238.980 68.230 ;
        RECT 238.700 67.900 238.980 68.180 ;
        RECT 238.700 67.900 239.540 68.180 ;
        RECT 239.260 34.810 239.540 35.190 ;
        RECT 239.260 34.860 239.540 35.140 ;
        RECT 239.260 34.860 239.540 68.180 ;
        RECT 239.260 60.060 243.460 60.340 ;
        RECT 243.180 60.010 243.460 60.390 ;
        RECT 243.180 60.060 243.460 60.340 ;
        RECT 186.620 46.010 186.900 46.390 ;
        RECT 186.620 40.410 186.900 40.790 ;
        RECT 186.620 40.460 186.900 40.740 ;
        RECT 186.620 40.460 186.900 46.340 ;
        RECT 186.620 46.060 186.900 46.340 ;
        RECT 149.100 99.210 149.380 99.590 ;
        RECT 147.420 107.050 147.700 107.430 ;
        RECT 147.420 107.100 147.700 107.380 ;
        RECT 147.420 107.100 149.380 107.380 ;
        RECT 149.100 57.210 149.380 57.590 ;
        RECT 149.100 57.260 149.380 57.540 ;
        RECT 149.100 57.260 149.380 99.540 ;
        RECT 149.100 99.260 149.380 99.540 ;
        RECT 149.100 99.260 149.380 107.380 ;
        RECT 238.700 50.490 238.980 50.870 ;
        RECT 238.140 35.370 238.420 35.750 ;
        RECT 238.140 35.420 238.420 35.700 ;
        RECT 238.140 35.420 238.980 35.700 ;
        RECT 238.700 35.420 238.980 50.820 ;
        RECT 238.700 50.540 238.980 50.820 ;
        RECT 251.020 57.770 251.300 58.150 ;
        RECT 251.020 29.210 251.300 29.590 ;
        RECT 251.020 29.260 251.300 29.540 ;
        RECT 251.020 29.260 251.300 50.820 ;
        RECT 251.020 50.490 251.300 50.870 ;
        RECT 251.020 50.540 251.300 50.820 ;
        RECT 251.020 50.540 251.300 58.100 ;
        RECT 251.020 57.820 251.300 58.100 ;
        RECT 130.620 84.090 130.900 84.470 ;
        RECT 130.620 84.140 130.900 84.420 ;
        RECT 130.620 84.140 131.460 84.420 ;
        RECT 131.180 51.050 131.460 51.430 ;
        RECT 131.180 51.100 131.460 51.380 ;
        RECT 131.180 51.100 131.460 84.420 ;
        RECT 156.380 99.210 156.660 99.590 ;
        RECT 156.380 40.410 156.660 40.790 ;
        RECT 156.380 40.460 156.660 40.740 ;
        RECT 156.380 40.460 156.660 88.900 ;
        RECT 156.380 88.570 156.660 88.950 ;
        RECT 156.380 88.620 156.660 88.900 ;
        RECT 156.380 88.620 156.660 99.540 ;
        RECT 156.380 99.260 156.660 99.540 ;
        RECT 233.100 60.010 233.380 60.390 ;
        RECT 232.540 41.530 232.820 41.910 ;
        RECT 232.540 41.580 232.820 41.860 ;
        RECT 232.540 41.580 232.820 60.340 ;
        RECT 232.540 47.690 232.820 48.070 ;
        RECT 232.540 47.740 232.820 48.020 ;
        RECT 232.540 60.060 233.380 60.340 ;
        RECT 233.100 60.060 233.380 60.340 ;
        RECT 275.100 38.170 275.380 38.550 ;
        RECT 273.980 38.220 274.260 47.460 ;
        RECT 273.980 38.220 275.380 38.500 ;
        RECT 273.980 47.130 274.260 47.510 ;
        RECT 273.980 47.180 274.260 47.460 ;
        RECT 273.980 47.180 274.260 66.500 ;
        RECT 273.980 66.220 277.060 66.500 ;
        RECT 275.100 38.220 275.380 38.500 ;
        RECT 276.780 66.170 277.060 66.550 ;
        RECT 276.780 66.220 277.060 66.500 ;
        RECT 133.980 37.610 134.260 37.990 ;
        RECT 133.420 29.770 133.700 30.150 ;
        RECT 133.420 29.820 133.700 30.100 ;
        RECT 133.420 29.820 134.260 30.100 ;
        RECT 133.980 29.820 134.260 37.940 ;
        RECT 133.980 37.660 134.260 37.940 ;
        RECT 133.980 37.660 134.820 37.940 ;
        RECT 134.540 37.660 134.820 47.460 ;
        RECT 134.540 47.130 134.820 47.510 ;
        RECT 134.540 47.180 134.820 47.460 ;
        RECT 161.420 59.450 161.700 59.830 ;
        RECT 161.420 50.490 161.700 50.870 ;
        RECT 161.420 50.540 161.700 50.820 ;
        RECT 161.420 50.540 161.700 59.780 ;
        RECT 161.420 59.500 161.700 59.780 ;
        RECT 115.500 52.730 115.780 53.110 ;
        RECT 115.500 41.530 115.780 41.910 ;
        RECT 115.500 41.580 115.780 41.860 ;
        RECT 115.500 41.580 115.780 53.060 ;
        RECT 115.500 52.780 115.780 53.060 ;
        RECT 123.340 99.210 123.620 99.590 ;
        RECT 121.660 51.050 121.940 51.430 ;
        RECT 121.660 51.100 121.940 51.380 ;
        RECT 121.660 51.100 121.940 99.540 ;
        RECT 121.660 99.260 123.620 99.540 ;
        RECT 123.340 99.260 123.620 99.540 ;
        RECT 123.340 99.260 123.620 103.460 ;
        RECT 123.340 103.180 126.420 103.460 ;
        RECT 126.140 103.130 126.420 103.510 ;
        RECT 126.140 103.180 126.420 103.460 ;
        RECT 168.140 44.890 168.420 45.270 ;
        RECT 168.140 44.940 168.420 45.220 ;
        RECT 168.140 44.940 168.420 98.420 ;
        RECT 168.140 64.490 168.420 64.870 ;
        RECT 168.140 64.540 168.420 64.820 ;
        RECT 168.140 98.090 168.420 98.470 ;
        RECT 168.140 98.140 168.420 98.420 ;
        RECT 248.780 45.450 249.060 45.830 ;
        RECT 248.780 45.500 249.060 45.780 ;
        RECT 248.780 45.500 249.620 45.780 ;
        RECT 249.340 45.500 249.620 62.580 ;
        RECT 249.340 48.810 249.620 49.190 ;
        RECT 249.340 48.860 249.620 49.140 ;
        RECT 249.340 62.250 249.620 62.630 ;
        RECT 249.340 62.300 249.620 62.580 ;
        RECT 281.820 91.370 282.100 91.750 ;
        RECT 279.580 50.490 279.860 50.870 ;
        RECT 279.580 50.540 279.860 50.820 ;
        RECT 279.580 50.540 279.860 91.700 ;
        RECT 279.580 91.420 282.100 91.700 ;
        RECT 281.820 91.420 282.100 91.700 ;
        RECT 109.900 60.570 110.180 60.950 ;
        RECT 109.900 57.770 110.180 58.150 ;
        RECT 109.900 57.820 110.180 58.100 ;
        RECT 109.900 57.820 110.180 60.900 ;
        RECT 109.900 60.620 110.180 60.900 ;
        RECT 142.940 56.650 143.220 57.030 ;
        RECT 141.820 57.820 142.100 59.780 ;
        RECT 141.820 57.820 142.660 58.100 ;
        RECT 141.820 59.450 142.100 59.830 ;
        RECT 141.820 59.500 142.100 59.780 ;
        RECT 142.380 56.700 142.660 58.100 ;
        RECT 142.380 56.700 143.220 56.980 ;
        RECT 142.940 56.700 143.220 56.980 ;
        RECT 165.340 60.570 165.620 60.950 ;
        RECT 165.340 56.650 165.620 57.030 ;
        RECT 165.340 56.700 165.620 56.980 ;
        RECT 165.340 56.700 165.620 60.900 ;
        RECT 165.340 60.620 165.620 60.900 ;
        RECT 274.540 99.210 274.820 99.590 ;
        RECT 274.540 67.290 274.820 67.670 ;
        RECT 274.540 67.340 274.820 67.620 ;
        RECT 274.540 67.340 274.820 99.540 ;
        RECT 274.540 99.260 274.820 99.540 ;
        RECT 149.100 22.490 149.380 22.870 ;
        RECT 149.100 22.540 149.380 22.820 ;
        RECT 149.100 22.540 149.380 47.460 ;
        RECT 149.100 47.130 149.380 47.510 ;
        RECT 149.100 47.180 149.380 47.460 ;
        RECT 200.060 57.210 200.340 57.590 ;
        RECT 199.500 52.730 199.780 53.110 ;
        RECT 199.500 52.780 199.780 53.060 ;
        RECT 199.500 52.780 200.340 53.060 ;
        RECT 200.060 52.780 200.340 57.540 ;
        RECT 200.060 57.260 200.340 57.540 ;
        RECT 250.460 60.570 250.740 60.950 ;
        RECT 250.460 56.650 250.740 57.030 ;
        RECT 250.460 56.700 250.740 56.980 ;
        RECT 250.460 56.700 250.740 60.900 ;
        RECT 250.460 60.620 250.740 60.900 ;
        RECT 112.700 33.130 112.980 33.510 ;
        RECT 112.700 33.180 112.980 33.460 ;
        RECT 112.700 33.180 112.980 39.620 ;
        RECT 112.700 39.340 113.540 39.620 ;
        RECT 113.260 39.290 113.540 39.670 ;
        RECT 113.260 39.340 113.540 39.620 ;
        RECT 173.740 65.050 174.020 65.430 ;
        RECT 172.620 62.250 172.900 62.630 ;
        RECT 172.620 62.300 172.900 62.580 ;
        RECT 172.620 62.300 172.900 65.380 ;
        RECT 172.620 65.100 174.020 65.380 ;
        RECT 173.740 65.100 174.020 65.380 ;
        RECT 195.020 37.050 195.300 37.430 ;
        RECT 195.020 37.100 195.300 37.380 ;
        RECT 195.020 37.100 195.300 65.380 ;
        RECT 195.020 65.050 195.300 65.430 ;
        RECT 195.020 65.100 195.300 65.380 ;
        RECT 95.900 58.890 96.180 59.270 ;
        RECT 95.900 44.330 96.180 44.710 ;
        RECT 95.900 44.380 96.180 44.660 ;
        RECT 95.900 44.380 96.180 59.220 ;
        RECT 95.900 58.940 96.180 59.220 ;
        RECT 104.860 54.410 105.140 54.790 ;
        RECT 104.860 46.010 105.140 46.390 ;
        RECT 104.860 46.060 105.140 46.340 ;
        RECT 104.860 46.060 105.140 54.740 ;
        RECT 104.860 54.460 105.140 54.740 ;
        RECT 125.580 57.770 125.860 58.150 ;
        RECT 123.340 56.650 123.620 57.030 ;
        RECT 123.340 56.700 123.620 56.980 ;
        RECT 123.340 56.700 123.620 58.100 ;
        RECT 123.340 57.820 125.860 58.100 ;
        RECT 125.580 57.820 125.860 58.100 ;
        RECT 173.180 60.570 173.460 60.950 ;
        RECT 171.500 51.610 171.780 51.990 ;
        RECT 171.500 51.660 171.780 51.940 ;
        RECT 171.500 51.660 171.780 60.900 ;
        RECT 171.500 60.620 173.460 60.900 ;
        RECT 173.180 60.620 173.460 60.900 ;
        RECT 262.780 44.890 263.060 45.270 ;
        RECT 262.780 33.130 263.060 33.510 ;
        RECT 262.780 33.180 263.060 33.460 ;
        RECT 262.780 33.180 263.060 45.220 ;
        RECT 262.780 44.940 263.060 45.220 ;
        RECT 198.380 89.130 198.660 89.510 ;
        RECT 197.820 71.210 198.100 71.590 ;
        RECT 197.820 71.260 198.100 71.540 ;
        RECT 197.820 71.260 198.660 71.540 ;
        RECT 198.380 71.260 198.660 89.460 ;
        RECT 198.380 89.180 198.660 89.460 ;
        RECT 226.380 95.850 226.660 96.230 ;
        RECT 226.380 89.690 226.660 90.070 ;
        RECT 226.380 89.740 226.660 90.020 ;
        RECT 226.380 89.740 226.660 96.180 ;
        RECT 226.380 95.900 226.660 96.180 ;
        RECT 183.260 68.410 183.540 68.790 ;
        RECT 183.260 58.890 183.540 59.270 ;
        RECT 183.260 58.940 183.540 59.220 ;
        RECT 183.260 58.940 183.540 68.740 ;
        RECT 183.260 68.460 183.540 68.740 ;
        RECT 249.900 46.010 250.180 46.390 ;
        RECT 249.900 46.060 250.180 46.340 ;
        RECT 249.900 46.060 250.740 46.340 ;
        RECT 250.460 46.060 250.740 55.300 ;
        RECT 250.460 54.970 250.740 55.350 ;
        RECT 250.460 55.020 250.740 55.300 ;
        RECT 124.460 99.770 124.740 100.150 ;
        RECT 124.460 80.170 124.740 80.550 ;
        RECT 124.460 80.220 124.740 80.500 ;
        RECT 124.460 80.220 124.740 100.100 ;
        RECT 124.460 99.820 124.740 100.100 ;
        RECT 173.740 46.010 174.020 46.390 ;
        RECT 173.740 46.060 174.020 46.340 ;
        RECT 173.740 46.060 174.020 49.140 ;
        RECT 173.740 48.810 174.020 49.190 ;
        RECT 173.740 48.860 174.020 49.140 ;
        RECT 176.540 48.810 176.820 49.190 ;
        RECT 176.540 48.860 176.820 49.140 ;
        RECT 176.540 48.860 176.820 66.500 ;
        RECT 176.540 66.170 176.820 66.550 ;
        RECT 176.540 66.220 176.820 66.500 ;
        RECT 176.540 66.220 176.820 80.500 ;
        RECT 176.540 80.170 176.820 80.550 ;
        RECT 176.540 80.220 176.820 80.500 ;
        RECT 171.500 99.770 171.780 100.150 ;
        RECT 171.500 72.890 171.780 73.270 ;
        RECT 171.500 72.940 171.780 73.220 ;
        RECT 171.500 72.940 171.780 100.100 ;
        RECT 171.500 99.820 171.780 100.100 ;
        RECT 208.460 38.170 208.740 38.550 ;
        RECT 208.460 38.220 208.740 38.500 ;
        RECT 208.460 38.220 209.300 38.500 ;
        RECT 209.020 38.220 209.300 49.140 ;
        RECT 209.020 48.810 209.300 49.190 ;
        RECT 209.020 48.860 209.300 49.140 ;
        RECT 229.180 48.810 229.460 49.190 ;
        RECT 229.180 36.490 229.460 36.870 ;
        RECT 229.180 36.540 229.460 36.820 ;
        RECT 229.180 36.540 229.460 49.140 ;
        RECT 229.180 48.860 229.460 49.140 ;
        RECT 210.140 71.770 210.420 72.150 ;
        RECT 210.140 33.690 210.420 34.070 ;
        RECT 210.140 33.740 210.420 34.020 ;
        RECT 210.140 33.740 210.420 72.100 ;
        RECT 210.140 71.820 210.420 72.100 ;
        RECT 212.380 82.970 212.660 83.350 ;
        RECT 212.380 33.690 212.660 34.070 ;
        RECT 212.380 33.740 212.660 34.020 ;
        RECT 212.380 33.740 212.660 83.300 ;
        RECT 212.380 83.020 212.660 83.300 ;
        RECT 118.300 115.450 118.580 115.830 ;
        RECT 118.300 105.930 118.580 106.310 ;
        RECT 118.300 105.980 118.580 106.260 ;
        RECT 118.300 105.980 118.580 115.780 ;
        RECT 118.300 115.500 118.580 115.780 ;
        RECT 234.780 84.090 235.060 84.470 ;
        RECT 234.780 70.090 235.060 70.470 ;
        RECT 234.780 70.140 235.060 70.420 ;
        RECT 234.780 70.140 235.060 84.420 ;
        RECT 234.780 84.140 235.060 84.420 ;
        RECT 191.660 107.610 191.940 107.990 ;
        RECT 191.660 107.660 191.940 107.940 ;
        RECT 191.660 107.660 192.500 107.940 ;
        RECT 192.220 90.250 192.500 90.630 ;
        RECT 192.220 90.300 192.500 90.580 ;
        RECT 192.220 90.300 192.500 107.940 ;
        RECT 204.540 107.610 204.820 107.990 ;
        RECT 203.980 103.690 204.260 104.070 ;
        RECT 203.980 103.740 204.260 104.020 ;
        RECT 203.980 103.740 204.260 107.940 ;
        RECT 203.980 107.660 204.820 107.940 ;
        RECT 204.540 107.660 204.820 107.940 ;
        RECT 240.380 123.290 240.660 123.670 ;
        RECT 236.460 81.850 236.740 82.230 ;
        RECT 236.460 81.900 236.740 82.180 ;
        RECT 236.460 81.900 236.740 123.620 ;
        RECT 236.460 123.340 240.660 123.620 ;
        RECT 240.380 123.340 240.660 123.620 ;
        RECT 81.340 52.730 81.620 53.110 ;
        RECT 81.340 40.970 81.620 41.350 ;
        RECT 81.340 41.020 81.620 41.300 ;
        RECT 81.340 41.020 81.620 53.060 ;
        RECT 81.340 52.780 81.620 53.060 ;
        RECT 243.180 108.730 243.460 109.110 ;
        RECT 242.060 115.500 242.340 118.020 ;
        RECT 242.060 115.500 242.900 115.780 ;
        RECT 242.060 117.690 242.340 118.070 ;
        RECT 242.060 117.740 242.340 118.020 ;
        RECT 242.620 108.780 242.900 115.780 ;
        RECT 242.620 108.780 243.460 109.060 ;
        RECT 243.180 108.780 243.460 109.060 ;
        RECT 194.460 84.090 194.740 84.470 ;
        RECT 194.460 75.740 194.740 84.420 ;
        RECT 194.460 75.740 195.300 76.020 ;
        RECT 194.460 84.140 194.740 84.420 ;
        RECT 195.020 74.570 195.300 74.950 ;
        RECT 195.020 74.620 195.300 74.900 ;
        RECT 195.020 74.620 195.300 76.020 ;
        RECT 80.780 84.090 81.060 84.470 ;
        RECT 80.780 84.140 81.060 84.420 ;
        RECT 80.780 84.140 82.180 84.420 ;
        RECT 81.900 52.220 82.180 84.420 ;
        RECT 81.900 52.220 82.740 52.500 ;
        RECT 82.460 52.170 82.740 52.550 ;
        RECT 82.460 52.220 82.740 52.500 ;
        RECT 224.700 93.050 224.980 93.430 ;
        RECT 224.700 93.100 224.980 93.380 ;
        RECT 224.700 93.100 225.540 93.380 ;
        RECT 225.260 93.100 225.540 114.660 ;
        RECT 225.260 114.330 225.540 114.710 ;
        RECT 225.260 114.380 225.540 114.660 ;
        RECT 278.460 84.090 278.740 84.470 ;
        RECT 278.460 52.220 278.740 84.420 ;
        RECT 278.460 52.220 279.300 52.500 ;
        RECT 278.460 84.140 278.740 84.420 ;
        RECT 279.020 52.170 279.300 52.550 ;
        RECT 279.020 52.220 279.300 52.500 ;
        RECT 113.820 79.050 114.100 79.430 ;
        RECT 110.460 79.050 110.740 79.430 ;
        RECT 110.460 79.100 110.740 79.380 ;
        RECT 110.460 79.100 114.100 79.380 ;
        RECT 113.820 79.100 114.100 79.380 ;
        RECT 150.780 84.090 151.060 84.470 ;
        RECT 150.780 79.050 151.060 79.430 ;
        RECT 150.780 79.100 151.060 79.380 ;
        RECT 150.780 79.100 151.060 84.420 ;
        RECT 150.780 84.140 151.060 84.420 ;
        RECT 156.940 77.370 157.220 77.750 ;
        RECT 156.940 77.420 157.220 77.700 ;
        RECT 156.940 77.420 157.220 91.140 ;
        RECT 156.940 90.810 157.220 91.190 ;
        RECT 156.940 90.860 157.220 91.140 ;
        RECT 265.020 107.610 265.300 107.990 ;
        RECT 265.020 107.660 265.300 107.940 ;
        RECT 265.020 107.660 265.860 107.940 ;
        RECT 265.580 91.420 265.860 107.940 ;
        RECT 265.580 91.420 266.420 91.700 ;
        RECT 266.140 91.370 266.420 91.750 ;
        RECT 266.140 91.420 266.420 91.700 ;
        RECT 215.740 88.010 216.020 88.390 ;
        RECT 215.740 88.060 216.020 88.340 ;
        RECT 215.740 88.060 216.020 91.140 ;
        RECT 215.740 90.810 216.020 91.190 ;
        RECT 215.740 90.860 216.020 91.140 ;
        RECT 159.740 102.010 160.020 102.390 ;
        RECT 159.740 91.370 160.020 91.750 ;
        RECT 159.740 91.420 160.020 91.700 ;
        RECT 159.740 91.420 160.020 102.340 ;
        RECT 159.740 102.060 160.020 102.340 ;
        RECT 163.660 84.090 163.940 84.470 ;
        RECT 163.660 84.140 163.940 84.420 ;
        RECT 163.660 84.140 165.060 84.420 ;
        RECT 164.780 80.780 165.060 84.420 ;
        RECT 164.780 80.780 166.180 81.060 ;
        RECT 165.900 75.690 166.180 76.070 ;
        RECT 165.900 75.740 166.180 76.020 ;
        RECT 165.900 75.740 166.180 81.060 ;
        RECT 247.660 70.090 247.940 70.470 ;
        RECT 247.660 70.140 247.940 70.420 ;
        RECT 247.660 70.140 247.940 96.740 ;
        RECT 247.660 96.410 247.940 96.790 ;
        RECT 247.660 96.460 247.940 96.740 ;
        RECT 123.900 72.330 124.180 72.710 ;
        RECT 123.900 72.380 124.180 72.660 ;
        RECT 123.900 72.380 124.740 72.660 ;
        RECT 124.460 61.690 124.740 62.070 ;
        RECT 124.460 61.740 124.740 62.020 ;
        RECT 124.460 61.740 124.740 72.660 ;
        RECT 243.180 115.450 243.460 115.830 ;
        RECT 243.180 115.500 243.460 115.780 ;
        RECT 243.180 115.500 244.020 115.780 ;
        RECT 243.740 79.610 244.020 79.990 ;
        RECT 243.740 79.660 244.020 79.940 ;
        RECT 243.740 79.660 244.020 115.780 ;
        RECT 65.100 115.450 65.380 115.830 ;
        RECT 65.100 115.500 65.380 115.780 ;
        RECT 65.100 115.500 65.940 115.780 ;
        RECT 65.660 91.370 65.940 91.750 ;
        RECT 65.660 91.420 65.940 91.700 ;
        RECT 65.660 91.420 65.940 115.780 ;
        RECT 163.100 113.770 163.380 114.150 ;
        RECT 163.100 82.970 163.380 83.350 ;
        RECT 163.100 83.020 163.380 83.300 ;
        RECT 163.100 83.020 163.380 114.100 ;
        RECT 163.100 113.820 163.380 114.100 ;
        RECT 242.620 63.930 242.900 64.310 ;
        RECT 242.620 63.980 242.900 64.260 ;
        RECT 242.620 63.980 242.900 67.060 ;
        RECT 242.620 66.730 242.900 67.110 ;
        RECT 242.620 66.780 242.900 67.060 ;
        RECT 242.620 79.050 242.900 79.430 ;
        RECT 242.620 79.100 242.900 79.380 ;
        RECT 242.620 79.100 243.460 79.380 ;
        RECT 243.180 75.740 243.460 79.380 ;
        RECT 243.180 75.740 244.020 76.020 ;
        RECT 243.740 75.690 244.020 76.070 ;
        RECT 243.740 75.740 244.020 76.020 ;
        RECT 206.780 115.450 207.060 115.830 ;
        RECT 206.780 115.500 207.060 115.780 ;
        RECT 206.780 115.500 207.620 115.780 ;
        RECT 207.340 99.210 207.620 99.590 ;
        RECT 207.340 99.260 207.620 99.540 ;
        RECT 207.340 99.260 207.620 115.780 ;
        RECT 56.700 46.010 56.980 46.390 ;
        RECT 56.140 60.620 56.420 63.140 ;
        RECT 56.140 60.620 56.980 60.900 ;
        RECT 56.140 62.810 56.420 63.190 ;
        RECT 56.140 62.860 56.420 63.140 ;
        RECT 56.700 46.060 56.980 46.340 ;
        RECT 56.700 46.060 56.980 60.900 ;
        RECT 224.140 131.130 224.420 131.510 ;
        RECT 223.580 118.810 223.860 119.190 ;
        RECT 223.580 118.860 223.860 119.140 ;
        RECT 223.580 118.860 223.860 131.460 ;
        RECT 223.580 131.180 224.420 131.460 ;
        RECT 224.140 131.180 224.420 131.460 ;
        RECT 212.380 91.930 212.660 92.310 ;
        RECT 211.820 75.690 212.100 76.070 ;
        RECT 211.820 75.740 212.100 76.020 ;
        RECT 211.820 75.740 212.100 92.260 ;
        RECT 211.820 91.980 212.660 92.260 ;
        RECT 212.380 91.980 212.660 92.260 ;
        RECT 69.580 33.690 69.860 34.070 ;
        RECT 67.900 33.740 68.180 64.260 ;
        RECT 67.900 33.740 69.860 34.020 ;
        RECT 67.900 63.930 68.180 64.310 ;
        RECT 67.900 63.980 68.180 64.260 ;
        RECT 69.580 33.740 69.860 34.020 ;
        RECT 193.900 123.290 194.180 123.670 ;
        RECT 193.900 101.450 194.180 101.830 ;
        RECT 193.900 101.500 194.180 101.780 ;
        RECT 193.900 101.500 194.180 123.620 ;
        RECT 193.900 123.340 194.180 123.620 ;
        RECT 205.660 101.450 205.940 101.830 ;
        RECT 205.660 90.860 205.940 101.780 ;
        RECT 205.660 90.860 206.500 91.140 ;
        RECT 205.660 101.500 205.940 101.780 ;
        RECT 206.220 90.810 206.500 91.190 ;
        RECT 206.220 90.860 206.500 91.140 ;
        RECT 196.140 76.250 196.420 76.630 ;
        RECT 196.140 60.010 196.420 60.390 ;
        RECT 196.140 60.060 196.420 60.340 ;
        RECT 196.140 60.060 196.420 76.580 ;
        RECT 196.140 76.300 196.420 76.580 ;
        RECT 147.420 29.210 147.700 29.590 ;
        RECT 147.420 18.570 147.700 18.950 ;
        RECT 147.420 18.620 147.700 18.900 ;
        RECT 147.420 18.620 147.700 29.540 ;
        RECT 147.420 29.260 147.700 29.540 ;
        RECT 193.340 131.130 193.620 131.510 ;
        RECT 193.340 122.170 193.620 122.550 ;
        RECT 193.340 122.220 193.620 122.500 ;
        RECT 193.340 122.220 193.620 131.460 ;
        RECT 193.340 131.180 193.620 131.460 ;
        RECT 185.500 100.890 185.780 101.270 ;
        RECT 185.500 80.170 185.780 80.550 ;
        RECT 185.500 80.220 185.780 80.500 ;
        RECT 185.500 80.220 185.780 101.220 ;
        RECT 185.500 100.940 185.780 101.220 ;
        RECT 146.300 68.970 146.580 69.350 ;
        RECT 144.060 17.450 144.340 17.830 ;
        RECT 144.060 17.500 144.340 17.780 ;
        RECT 144.060 17.500 144.340 69.300 ;
        RECT 144.060 69.020 146.580 69.300 ;
        RECT 146.300 69.020 146.580 69.300 ;
        RECT 189.420 52.730 189.700 53.110 ;
        RECT 189.420 35.930 189.700 36.310 ;
        RECT 189.420 35.980 189.700 36.260 ;
        RECT 189.420 35.980 189.700 53.060 ;
        RECT 189.420 52.780 189.700 53.060 ;
        RECT 150.780 37.050 151.060 37.430 ;
        RECT 150.780 37.100 151.060 37.380 ;
        RECT 150.780 37.100 151.620 37.380 ;
        RECT 151.340 37.100 151.620 117.460 ;
        RECT 151.340 40.410 151.620 40.790 ;
        RECT 151.340 40.460 151.620 40.740 ;
        RECT 151.340 117.130 151.620 117.510 ;
        RECT 151.340 117.180 151.620 117.460 ;
        RECT 146.300 14.650 146.580 15.030 ;
        RECT 145.740 14.700 146.020 36.820 ;
        RECT 145.740 14.700 146.580 14.980 ;
        RECT 145.740 36.490 146.020 36.870 ;
        RECT 145.740 36.540 146.020 36.820 ;
        RECT 146.300 14.700 146.580 14.980 ;
        RECT 200.060 118.810 200.340 119.190 ;
        RECT 200.060 118.860 200.340 119.140 ;
        RECT 200.060 118.860 200.340 126.420 ;
        RECT 200.060 126.090 200.340 126.470 ;
        RECT 200.060 126.140 200.340 126.420 ;
        RECT 83.020 76.810 83.300 77.190 ;
        RECT 82.460 61.130 82.740 61.510 ;
        RECT 82.460 61.180 82.740 61.460 ;
        RECT 82.460 61.180 83.300 61.460 ;
        RECT 83.020 61.180 83.300 77.140 ;
        RECT 83.020 76.860 83.300 77.140 ;
        RECT 83.020 76.860 83.300 112.980 ;
        RECT 83.020 112.650 83.300 113.030 ;
        RECT 83.020 112.700 83.300 112.980 ;
        RECT 158.060 113.770 158.340 114.150 ;
        RECT 158.060 113.820 158.340 114.100 ;
        RECT 158.060 113.820 158.900 114.100 ;
        RECT 158.620 42.650 158.900 43.030 ;
        RECT 158.620 42.700 158.900 42.980 ;
        RECT 158.620 42.700 158.900 114.100 ;
        RECT 184.380 21.930 184.660 22.310 ;
        RECT 184.380 21.980 184.660 22.260 ;
        RECT 184.380 21.980 184.660 36.260 ;
        RECT 184.380 35.930 184.660 36.310 ;
        RECT 184.380 35.980 184.660 36.260 ;
        RECT 84.140 66.170 84.420 66.550 ;
        RECT 84.140 10.170 84.420 10.550 ;
        RECT 84.140 10.220 84.420 10.500 ;
        RECT 84.140 10.220 84.420 66.500 ;
        RECT 84.140 66.220 84.420 66.500 ;
        RECT 84.140 66.220 84.420 102.900 ;
        RECT 84.140 102.570 84.420 102.950 ;
        RECT 84.140 102.620 84.420 102.900 ;
        RECT 125.020 115.450 125.300 115.830 ;
        RECT 122.780 103.690 123.060 104.070 ;
        RECT 122.780 103.740 123.060 104.020 ;
        RECT 122.780 103.740 123.060 115.780 ;
        RECT 122.780 115.500 125.300 115.780 ;
        RECT 125.020 115.500 125.300 115.780 ;
        RECT 91.980 12.970 92.260 13.350 ;
        RECT 91.980 13.020 92.260 13.300 ;
        RECT 91.980 13.020 92.820 13.300 ;
        RECT 92.540 13.020 92.820 56.420 ;
        RECT 92.540 56.140 93.380 56.420 ;
        RECT 93.100 56.140 93.380 100.660 ;
        RECT 93.100 100.380 93.940 100.660 ;
        RECT 93.660 100.380 93.940 101.780 ;
        RECT 93.660 101.450 93.940 101.830 ;
        RECT 93.660 101.500 93.940 101.780 ;
        RECT 63.420 51.610 63.700 51.990 ;
        RECT 63.420 51.660 63.700 51.940 ;
        RECT 63.420 51.660 64.820 51.940 ;
        RECT 64.540 41.580 64.820 51.940 ;
        RECT 64.540 41.580 66.500 41.860 ;
        RECT 66.220 41.580 66.500 43.540 ;
        RECT 66.220 43.210 66.500 43.590 ;
        RECT 66.220 43.260 66.500 43.540 ;
        RECT 90.300 52.170 90.580 52.550 ;
        RECT 90.300 18.010 90.580 18.390 ;
        RECT 90.300 18.060 90.580 18.340 ;
        RECT 90.300 18.060 90.580 52.500 ;
        RECT 90.300 43.210 90.580 43.590 ;
        RECT 90.300 43.260 90.580 43.540 ;
        RECT 90.300 52.220 90.580 52.500 ;
        RECT 90.300 52.220 90.580 64.820 ;
        RECT 90.300 64.490 90.580 64.870 ;
        RECT 90.300 64.540 90.580 64.820 ;
        RECT 142.940 75.690 143.220 76.070 ;
        RECT 142.380 44.330 142.660 44.710 ;
        RECT 142.380 44.380 142.660 44.660 ;
        RECT 142.380 44.380 143.220 44.660 ;
        RECT 142.940 16.890 143.220 17.270 ;
        RECT 142.940 16.940 143.220 17.220 ;
        RECT 142.940 16.940 143.220 44.660 ;
        RECT 142.940 44.380 143.220 55.860 ;
        RECT 142.940 55.580 143.780 55.860 ;
        RECT 142.940 75.740 143.220 76.020 ;
        RECT 142.940 75.740 143.780 76.020 ;
        RECT 143.500 55.580 143.780 76.020 ;
        RECT 143.500 66.170 143.780 66.550 ;
        RECT 143.500 66.220 143.780 66.500 ;
        RECT 115.500 83.530 115.780 83.910 ;
        RECT 115.500 83.580 115.780 83.860 ;
        RECT 115.500 83.580 116.340 83.860 ;
        RECT 116.060 16.330 116.340 16.710 ;
        RECT 116.060 16.380 116.340 16.660 ;
        RECT 116.060 16.380 116.340 83.860 ;
        RECT 116.060 83.580 116.340 91.700 ;
        RECT 116.060 88.010 116.340 88.390 ;
        RECT 116.060 88.060 116.340 88.340 ;
        RECT 116.060 91.370 116.340 91.750 ;
        RECT 116.060 91.420 116.340 91.700 ;
        RECT 185.500 44.330 185.780 44.710 ;
        RECT 185.500 17.450 185.780 17.830 ;
        RECT 185.500 17.500 185.780 17.780 ;
        RECT 185.500 17.500 185.780 44.660 ;
        RECT 185.500 44.380 185.780 44.660 ;
        RECT 56.700 138.970 56.980 139.350 ;
        RECT 56.700 139.020 56.980 139.300 ;
        RECT 56.700 139.020 56.980 147.140 ;
        RECT 56.700 146.810 56.980 147.190 ;
        RECT 56.700 146.860 56.980 147.140 ;
        RECT 80.220 146.810 80.500 147.190 ;
        RECT 80.220 146.860 80.500 147.140 ;
        RECT 80.220 146.860 81.620 147.140 ;
        RECT 81.340 138.410 81.620 138.790 ;
        RECT 81.340 138.460 81.620 138.740 ;
        RECT 81.340 138.460 81.620 147.140 ;
        RECT 88.060 84.650 88.340 85.030 ;
        RECT 88.060 84.700 88.340 84.980 ;
        RECT 88.060 84.700 88.900 84.980 ;
        RECT 88.620 84.700 88.900 92.820 ;
        RECT 88.620 92.490 88.900 92.870 ;
        RECT 88.620 92.540 88.900 92.820 ;
        RECT 141.820 92.490 142.100 92.870 ;
        RECT 141.820 92.540 142.100 92.820 ;
        RECT 141.820 92.540 142.100 101.220 ;
        RECT 141.820 100.890 142.100 101.270 ;
        RECT 141.820 100.940 142.100 101.220 ;
        RECT 160.860 35.930 161.140 36.310 ;
        RECT 160.860 35.980 161.140 36.260 ;
        RECT 160.860 35.980 161.140 54.180 ;
        RECT 160.860 53.850 161.140 54.230 ;
        RECT 160.860 53.900 161.140 54.180 ;
        RECT 271.180 45.450 271.460 45.830 ;
        RECT 271.180 45.500 271.460 45.780 ;
        RECT 271.180 45.500 273.140 45.780 ;
        RECT 272.860 45.500 273.140 62.020 ;
        RECT 272.860 61.690 273.140 62.070 ;
        RECT 272.860 61.740 273.140 62.020 ;
        RECT 243.740 48.810 244.020 49.190 ;
        RECT 243.740 48.860 244.020 49.140 ;
        RECT 243.740 48.860 244.020 61.460 ;
        RECT 243.740 61.130 244.020 61.510 ;
        RECT 243.740 61.180 244.020 61.460 ;
        RECT 227.500 108.170 227.780 108.550 ;
        RECT 227.500 93.610 227.780 93.990 ;
        RECT 227.500 93.660 227.780 93.940 ;
        RECT 227.500 93.660 227.780 108.500 ;
        RECT 227.500 108.220 227.780 108.500 ;
        RECT 134.540 123.290 134.820 123.670 ;
        RECT 134.540 98.650 134.820 99.030 ;
        RECT 134.540 98.700 134.820 98.980 ;
        RECT 134.540 98.700 134.820 123.620 ;
        RECT 134.540 123.340 134.820 123.620 ;
        RECT 134.540 123.340 134.820 148.260 ;
        RECT 134.540 147.930 134.820 148.310 ;
        RECT 134.540 147.980 134.820 148.260 ;
        RECT 166.460 36.490 166.740 36.870 ;
        RECT 166.460 16.890 166.740 17.270 ;
        RECT 166.460 16.940 166.740 17.220 ;
        RECT 166.460 16.940 166.740 36.820 ;
        RECT 166.460 36.540 166.740 36.820 ;
        RECT 166.460 36.540 166.740 98.420 ;
        RECT 166.460 98.090 166.740 98.470 ;
        RECT 166.460 98.140 166.740 98.420 ;
        RECT 324.940 158.010 325.220 158.390 ;
        RECT 324.940 158.060 325.220 158.340 ;
        RECT 324.940 158.060 331.380 158.340 ;
        RECT 331.100 158.060 331.380 159.460 ;
        RECT 331.100 159.180 331.380 159.460 ;
        RECT 254.380 107.610 254.660 107.990 ;
        RECT 254.380 107.660 254.660 107.940 ;
        RECT 254.380 107.660 254.660 110.180 ;
        RECT 254.380 109.850 254.660 110.230 ;
        RECT 254.380 109.900 254.660 110.180 ;
        RECT 322.700 159.130 322.980 159.510 ;
        RECT 322.700 158.620 322.980 159.460 ;
        RECT 322.700 158.620 324.100 158.900 ;
        RECT 322.700 159.180 322.980 159.460 ;
        RECT 323.820 158.620 324.100 159.460 ;
        RECT 323.820 159.180 324.100 159.460 ;
        RECT 83.580 158.620 83.860 159.460 ;
        RECT 83.580 158.570 83.860 158.950 ;
        RECT 83.580 158.620 83.860 158.900 ;
        RECT 83.580 159.180 83.860 159.460 ;
        RECT 76.300 158.620 76.580 159.460 ;
        RECT 75.740 145.690 76.020 146.070 ;
        RECT 75.740 145.740 76.020 146.020 ;
        RECT 75.740 145.740 76.020 158.900 ;
        RECT 75.740 158.620 76.580 158.900 ;
        RECT 76.300 159.180 76.580 159.460 ;
        RECT 69.020 145.740 69.300 159.460 ;
        RECT 69.020 145.690 69.300 146.070 ;
        RECT 69.020 145.740 69.300 146.020 ;
        RECT 69.020 159.180 69.300 159.460 ;
        RECT 61.740 158.620 62.020 159.460 ;
        RECT 61.740 158.570 62.020 158.950 ;
        RECT 61.740 158.620 62.020 158.900 ;
        RECT 61.740 159.180 62.020 159.460 ;
        RECT 54.460 158.620 54.740 159.460 ;
        RECT 54.460 158.620 55.860 158.900 ;
        RECT 54.460 159.180 54.740 159.460 ;
        RECT 55.580 145.690 55.860 146.070 ;
        RECT 55.580 145.740 55.860 146.020 ;
        RECT 55.580 145.740 55.860 158.900 ;
        RECT 47.180 158.620 47.460 159.460 ;
        RECT 47.180 158.620 49.140 158.900 ;
        RECT 47.180 159.180 47.460 159.460 ;
        RECT 48.860 145.690 49.140 146.070 ;
        RECT 48.860 145.740 49.140 146.020 ;
        RECT 48.860 145.740 49.140 158.900 ;
        RECT 39.900 158.620 40.180 159.460 ;
        RECT 39.900 158.620 41.300 158.900 ;
        RECT 39.900 159.180 40.180 159.460 ;
        RECT 41.020 145.690 41.300 146.070 ;
        RECT 41.020 145.740 41.300 146.020 ;
        RECT 41.020 145.740 41.300 158.900 ;
        RECT 32.620 158.620 32.900 159.460 ;
        RECT 32.620 158.620 38.500 158.900 ;
        RECT 32.620 159.180 32.900 159.460 ;
        RECT 38.220 137.850 38.500 138.230 ;
        RECT 38.220 137.900 38.500 138.180 ;
        RECT 38.220 137.900 38.500 158.900 ;
        RECT 141.820 158.620 142.100 159.460 ;
        RECT 141.820 158.570 142.100 158.950 ;
        RECT 141.820 158.620 142.100 158.900 ;
        RECT 141.820 159.180 142.100 159.460 ;
        RECT 134.540 158.620 134.820 159.460 ;
        RECT 133.980 137.290 134.260 137.670 ;
        RECT 133.980 137.340 134.260 137.620 ;
        RECT 133.980 137.340 134.260 158.900 ;
        RECT 133.980 158.620 134.820 158.900 ;
        RECT 134.540 159.180 134.820 159.460 ;
        RECT 127.260 158.620 127.540 159.460 ;
        RECT 127.260 158.620 128.100 158.900 ;
        RECT 127.260 159.180 127.540 159.460 ;
        RECT 127.820 146.250 128.100 146.630 ;
        RECT 127.820 146.300 128.100 146.580 ;
        RECT 127.820 146.300 128.100 158.900 ;
        RECT 119.980 158.620 120.260 159.460 ;
        RECT 119.980 158.620 121.940 158.900 ;
        RECT 119.980 159.180 120.260 159.460 ;
        RECT 121.660 146.250 121.940 146.630 ;
        RECT 121.660 146.300 121.940 146.580 ;
        RECT 121.660 146.300 121.940 158.900 ;
        RECT 112.700 158.620 112.980 159.460 ;
        RECT 112.700 158.620 114.100 158.900 ;
        RECT 112.700 159.180 112.980 159.460 ;
        RECT 113.820 146.250 114.100 146.630 ;
        RECT 113.820 146.300 114.100 146.580 ;
        RECT 113.820 146.300 114.100 158.900 ;
        RECT 105.420 158.620 105.700 159.460 ;
        RECT 104.860 146.250 105.140 146.630 ;
        RECT 104.860 146.300 105.140 146.580 ;
        RECT 104.860 146.300 105.140 158.900 ;
        RECT 104.860 158.620 105.700 158.900 ;
        RECT 105.420 159.180 105.700 159.460 ;
        RECT 98.140 158.620 98.420 159.460 ;
        RECT 95.340 146.250 95.620 146.630 ;
        RECT 95.340 146.300 95.620 146.580 ;
        RECT 95.340 146.300 95.620 158.900 ;
        RECT 95.340 158.620 98.420 158.900 ;
        RECT 98.140 159.180 98.420 159.460 ;
        RECT 90.860 158.620 91.140 159.460 ;
        RECT 87.500 146.250 87.780 146.630 ;
        RECT 87.500 146.300 87.780 146.580 ;
        RECT 87.500 146.300 87.780 158.900 ;
        RECT 87.500 158.620 91.140 158.900 ;
        RECT 90.860 159.180 91.140 159.460 ;
        RECT 200.060 158.620 200.340 159.460 ;
        RECT 200.060 158.570 200.340 158.950 ;
        RECT 200.060 158.620 200.340 158.900 ;
        RECT 200.060 159.180 200.340 159.460 ;
        RECT 192.780 138.460 193.060 159.460 ;
        RECT 192.780 138.410 193.060 138.790 ;
        RECT 192.780 138.460 193.060 138.740 ;
        RECT 192.780 159.180 193.060 159.460 ;
        RECT 185.500 158.620 185.780 159.460 ;
        RECT 185.500 158.570 185.780 158.950 ;
        RECT 185.500 158.620 185.780 158.900 ;
        RECT 185.500 159.180 185.780 159.460 ;
        RECT 178.220 158.620 178.500 159.460 ;
        RECT 176.540 86.890 176.820 87.270 ;
        RECT 176.540 86.940 176.820 87.220 ;
        RECT 176.540 86.940 176.820 158.900 ;
        RECT 176.540 158.620 178.500 158.900 ;
        RECT 178.220 159.180 178.500 159.460 ;
        RECT 170.940 158.620 171.220 159.460 ;
        RECT 170.380 146.250 170.660 146.630 ;
        RECT 170.380 146.300 170.660 146.580 ;
        RECT 170.380 146.300 170.660 158.900 ;
        RECT 170.380 158.620 171.220 158.900 ;
        RECT 170.940 159.180 171.220 159.460 ;
        RECT 163.660 158.620 163.940 159.460 ;
        RECT 163.660 158.570 163.940 158.950 ;
        RECT 163.660 158.620 163.940 158.900 ;
        RECT 163.660 159.180 163.940 159.460 ;
        RECT 156.380 158.620 156.660 159.460 ;
        RECT 156.380 158.570 156.660 158.950 ;
        RECT 156.380 158.620 156.660 158.900 ;
        RECT 156.380 159.180 156.660 159.460 ;
        RECT 149.100 158.620 149.380 159.460 ;
        RECT 149.100 158.570 149.380 158.950 ;
        RECT 149.100 158.620 149.380 158.900 ;
        RECT 149.100 159.180 149.380 159.460 ;
  END
END tt_um_microlane_demo
END LIBRARY

